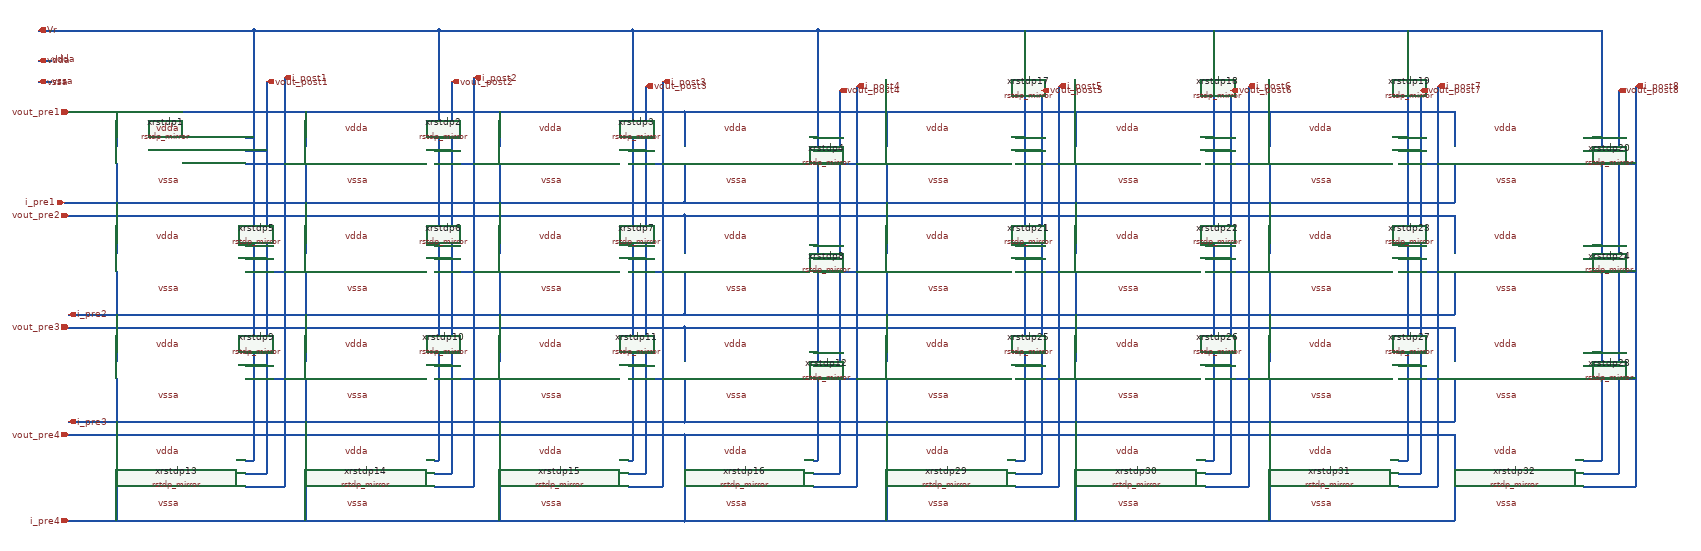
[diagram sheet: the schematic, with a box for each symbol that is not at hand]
v {xschem version=3.4.6RC file_version=1.2
}
G {}
K {}
V {}
S {}
E {}
N 1130 -130 1130 -50 {
lab=vout_pre1}
N -310 -130 1130 -130 {
lab=vout_pre1}
N 1130 110 1130 200 {
lab=vout_pre2}
N -300 110 1130 110 {
lab=vout_pre2}
N 1130 620 1130 700 {
lab=vout_pre4}
N -300 620 1130 620 {
lab=vout_pre4}
N -300 370 1130 370 {
lab=vout_pre3}
N 1130 370 1130 450 {
lab=vout_pre3}
N -190 -130 -190 -50 {
lab=vout_pre1}
N 250 -130 250 -50 {
lab=vout_pre1}
N 700 -130 700 -50 {
lab=vout_pre1}
N 700 110 700 200 {
lab=vout_pre2}
N 250 110 250 200 {
lab=vout_pre2}
N -190 110 -190 200 {
lab=vout_pre2}
N -190 370 -190 450 {
lab=vout_pre3}
N 250 370 250 450 {
lab=vout_pre3}
N 700 370 700 450 {
lab=vout_pre3}
N -190 620 -190 700 {
lab=vout_pre4}
N 250 620 250 700 {
lab=vout_pre4}
N 700 620 700 700 {
lab=vout_pre4}
N 160 -200 160 710 {
lab=vout_post1}
N 110 710 160 710 {
lab=vout_post1}
N 110 460 160 460 {
lab=vout_post1}
N 110 210 160 210 {
lab=vout_post1}
N 110 -40 160 -40 {
lab=vout_post1}
N 590 -200 590 710 {
lab=vout_post2}
N 550 710 590 710 {
lab=vout_post2}
N 550 460 590 460 {
lab=vout_post2}
N 550 210 590 210 {
lab=vout_post2}
N 550 -40 590 -40 {
lab=vout_post2}
N 1040 -190 1040 710 {
lab=vout_post3}
N 1000 710 1040 710 {
lab=vout_post3}
N 1000 460 1040 460 {
lab=vout_post3}
N 1000 210 1040 210 {
lab=vout_post3}
N 1000 -40 1040 -40 {
lab=vout_post3}
N 1490 -180 1490 710 {
lab=vout_post4}
N 1430 710 1490 710 {
lab=vout_post4}
N 1430 460 1490 460 {
lab=vout_post4}
N 1430 210 1490 210 {
lab=vout_post4}
N 1430 -40 1490 -40 {
lab=vout_post4}
N -310 80 1130 80 {
lab=i_pre1}
N 1130 -10 1130 80 {
lab=i_pre1}
N 700 -10 700 80 {
lab=i_pre1}
N 250 -10 250 80 {
lab=i_pre1}
N -190 -10 -190 80 {
lab=i_pre1}
N -300 340 1130 340 {
lab=i_pre2}
N 1130 240 1130 340 {
lab=i_pre2}
N 700 240 700 340 {
lab=i_pre2}
N 250 240 250 340 {
lab=i_pre2}
N -190 240 -190 340 {
lab=i_pre2}
N -300 820 1130 820 {
lab=i_pre4}
N 1130 740 1130 820 {
lab=i_pre4}
N 700 740 700 820 {
lab=i_pre4}
N 250 740 250 820 {
lab=i_pre4}
N -190 740 -190 820 {
lab=i_pre4}
N -300 590 1130 590 {
lab=i_pre3}
N 1130 490 1130 590 {
lab=i_pre3}
N 700 490 700 590 {
lab=i_pre3}
N 250 490 250 590 {
lab=i_pre3}
N -190 490 -190 590 {
lab=i_pre3}
N 200 -210 200 740 {
lab=i_post1}
N 110 740 200 740 {
lab=i_post1}
N 110 -10 200 -10 {
lab=i_post1}
N 110 240 200 240 {
lab=i_post1}
N 110 490 200 490 {
lab=i_post1}
N 640 -210 640 740 {
lab=i_post2}
N 550 740 640 740 {
lab=i_post2}
N 550 490 640 490 {
lab=i_post2}
N 550 240 640 240 {
lab=i_post2}
N 550 -10 640 -10 {
lab=i_post2}
N 1080 -200 1080 740 {
lab=i_post3}
N 1000 740 1080 740 {
lab=i_post3}
N 1000 490 1080 490 {
lab=i_post3}
N 1000 240 1080 240 {
lab=i_post3}
N 1000 -10 1080 -10 {
lab=i_post3}
N 1530 -190 1530 740 {
lab=i_post4}
N 1430 740 1530 740 {
lab=i_post4}
N 1430 490 1530 490 {
lab=i_post4}
N 1430 240 1530 240 {
lab=i_post4}
N 1430 -10 1530 -10 {
lab=i_post4}
N -370 -250 -340 -250 {
lab=vdda}
N -370 -200 -340 -200 {
lab=vssa}
N -370 -320 -350 -320 {
lab=Vr}
N 110 -70 120 -70 {
lab=Vr}
N 550 -70 560 -70 {
lab=Vr}
N 1000 -70 1010 -70 {
lab=Vr}
N 1430 -70 1440 -70 {
lab=Vr}
N 1430 180 1440 180 {
lab=Vr}
N 1000 180 1010 180 {
lab=Vr}
N 550 180 560 180 {
lab=Vr}
N 110 180 120 180 {
lab=Vr}
N 110 430 120 430 {
lab=Vr}
N 550 430 560 430 {
lab=Vr}
N 1000 430 1010 430 {
lab=Vr}
N 1430 430 1440 430 {
lab=Vr}
N 1430 680 1440 680 {
lab=Vr}
N 1000 680 1010 680 {
lab=Vr}
N 550 680 560 680 {
lab=Vr}
N 110 680 120 680 {
lab=Vr}
N -350 -320 130 -320 {
lab=Vr}
N 130 -320 130 680 {
lab=Vr}
N 120 680 130 680 {
lab=Vr}
N 120 430 130 430 {
lab=Vr}
N 120 180 130 180 {
lab=Vr}
N 120 -70 130 -70 {
lab=Vr}
N 560 -320 560 680 {
lab=Vr}
N 130 -320 560 -320 {
lab=Vr}
N 1010 -320 1010 680 {
lab=Vr}
N 560 -320 1010 -320 {
lab=Vr}
N 1440 -320 1440 680 {
lab=Vr}
N 1010 -320 1440 -320 {
lab=Vr}
N 1130 80 2920 80 {
lab=i_pre1}
N 2920 -10 2920 80 {
lab=i_pre1}
N 2490 -10 2490 80 {
lab=i_pre1}
N 2040 -10 2040 80 {
lab=i_pre1}
N 1600 -10 1600 80 {
lab=i_pre1}
N 1130 340 2920 340 {
lab=i_pre2}
N 2920 240 2920 340 {
lab=i_pre2}
N 2490 240 2490 340 {
lab=i_pre2}
N 2040 240 2040 340 {
lab=i_pre2}
N 1600 240 1600 340 {
lab=i_pre2}
N 1130 590 2920 590 {
lab=i_pre3}
N 2920 490 2920 590 {
lab=i_pre3}
N 2490 490 2490 590 {
lab=i_pre3}
N 2040 490 2040 590 {
lab=i_pre3}
N 1600 490 1600 590 {
lab=i_pre3}
N 1130 820 2920 820 {
lab=i_pre4}
N 2920 740 2920 820 {
lab=i_pre4}
N 2490 740 2490 820 {
lab=i_pre4}
N 2040 740 2040 820 {
lab=i_pre4}
N 1600 740 1600 820 {
lab=i_pre4}
N 1440 -320 3260 -320 {
lab=Vr}
N 3260 -320 3260 680 {
lab=Vr}
N 3220 680 3260 680 {
lab=Vr}
N 3220 430 3260 430 {
lab=Vr}
N 3220 180 3260 180 {
lab=Vr}
N 3220 -70 3260 -70 {
lab=Vr}
N 2810 -320 2810 680 {
lab=Vr}
N 2790 -70 2810 -70 {
lab=Vr}
N 2790 180 2810 180 {
lab=Vr}
N 2790 430 2810 430 {
lab=Vr}
N 2790 680 2810 680 {
lab=Vr}
N 2360 -320 2360 680 {
lab=Vr}
N 2340 680 2360 680 {
lab=Vr}
N 2340 430 2360 430 {
lab=Vr}
N 2340 180 2360 180 {
lab=Vr}
N 2340 -70 2360 -70 {
lab=Vr}
N 1920 -320 1920 680 {
lab=Vr}
N 1900 680 1920 680 {
lab=Vr}
N 1900 430 1920 430 {
lab=Vr}
N 1900 180 1920 180 {
lab=Vr}
N 1900 -70 1920 -70 {
lab=Vr}
N 1960 -180 1960 710 {
lab=vout_post5}
N 2000 -190 2000 740 {
lab=i_post5}
N 1900 -40 1960 -40 {
lab=vout_post5}
N 1900 -10 2000 -10 {
lab=i_post5}
N 1900 210 1960 210 {
lab=vout_post5}
N 1900 240 2000 240 {
lab=i_post5}
N 1900 460 1960 460 {
lab=vout_post5}
N 1900 490 2000 490 {
lab=i_post5}
N 1900 710 1960 710 {
lab=vout_post5}
N 1900 740 2000 740 {
lab=i_post5}
N 2400 -180 2400 710 {
lab=vout_post6}
N 2440 -190 2440 740 {
lab=i_post6}
N 2340 -40 2400 -40 {
lab=vout_post6}
N 2340 -10 2440 -10 {
lab=i_post6}
N 2340 210 2400 210 {
lab=vout_post6}
N 2340 240 2440 240 {
lab=i_post6}
N 2340 460 2400 460 {
lab=vout_post6}
N 2340 490 2440 490 {
lab=i_post6}
N 2340 710 2400 710 {
lab=vout_post6}
N 2340 740 2440 740 {
lab=i_post6}
N 2840 -180 2840 710 {
lab=vout_post7}
N 2880 -190 2880 740 {
lab=i_post7}
N 2790 -40 2840 -40 {
lab=vout_post7}
N 2790 -10 2880 -10 {
lab=i_post7}
N 2790 210 2840 210 {
lab=vout_post7}
N 2790 240 2880 240 {
lab=i_post7}
N 2790 460 2840 460 {
lab=vout_post7}
N 2790 490 2880 490 {
lab=i_post7}
N 2790 710 2840 710 {
lab=vout_post7}
N 2790 740 2880 740 {
lab=i_post7}
N 3300 -180 3300 710 {
lab=vout_post8}
N 3340 -190 3340 740 {
lab=i_post8}
N 3220 -40 3300 -40 {
lab=vout_post8}
N 3220 -10 3340 -10 {
lab=i_post8}
N 3220 210 3300 210 {
lab=vout_post8}
N 3220 240 3340 240 {
lab=i_post8}
N 3220 460 3300 460 {
lab=vout_post8}
N 3220 490 3340 490 {
lab=i_post8}
N 3220 710 3300 710 {
lab=vout_post8}
N 3220 740 3340 740 {
lab=i_post8}
N 1130 -130 2920 -130 {
lab=vout_pre1}
N 2920 -130 2920 -50 {
lab=vout_pre1}
N 1600 -130 1600 -50 {
lab=vout_pre1}
N 2040 -130 2040 -50 {
lab=vout_pre1}
N 2490 -130 2490 -50 {
lab=vout_pre1}
N 1130 110 2920 110 {
lab=vout_pre2}
N 1600 110 1600 200 {
lab=vout_pre2}
N 2040 110 2040 200 {
lab=vout_pre2}
N 2490 110 2490 200 {
lab=vout_pre2}
N 2920 110 2920 200 {
lab=vout_pre2}
N 1130 370 2920 370 {
lab=vout_pre3}
N 1600 370 1600 450 {
lab=vout_pre3}
N 2040 370 2040 450 {
lab=vout_pre3}
N 2490 370 2490 450 {
lab=vout_pre3}
N 2920 370 2920 450 {
lab=vout_pre3}
N 1130 620 2920 620 {
lab=vout_pre4}
N 1600 620 1600 700 {
lab=vout_pre4}
N 2040 620 2040 700 {
lab=vout_pre4}
N 2490 620 2490 700 {
lab=vout_pre4}
N 2920 620 2920 700 {
lab=vout_pre4}
C {Synapse/rstdp_mirror.sym} -40 -50 0 0 {name=xrstdp1}
C {devices/ipin.sym} -300 -130 0 0 {name=p1 lab=vout_pre1}
C {devices/opin.sym} 160 -200 3 0 {name=p5 lab=vout_post1}
C {devices/ipin.sym} -310 80 0 0 {name=p6 lab=i_pre1}
C {devices/iopin.sym} -370 -250 0 1 {name=p7 lab=vdda}
C {devices/iopin.sym} -370 -200 0 1 {name=p8 lab=vssa}
C {Synapse/rstdp_mirror.sym} 400 -50 0 0 {name=xrstdp2}
C {Synapse/rstdp_mirror.sym} 850 -50 0 0 {name=xrstdp3}
C {Synapse/rstdp_mirror.sym} 1280 -50 0 0 {name=xrstdp4}
C {devices/opin.sym} 200 -210 3 0 {name=p9 lab=i_post1}
C {Synapse/rstdp_mirror.sym} -40 200 0 0 {name=xrstdp5}
C {Synapse/rstdp_mirror.sym} 400 200 0 0 {name=xrstdp6}
C {Synapse/rstdp_mirror.sym} 850 200 0 0 {name=xrstdp7}
C {Synapse/rstdp_mirror.sym} 1280 200 0 0 {name=xrstdp8}
C {Synapse/rstdp_mirror.sym} -40 450 0 0 {name=xrstdp9}
C {Synapse/rstdp_mirror.sym} 400 450 0 0 {name=xrstdp10}
C {Synapse/rstdp_mirror.sym} 850 450 0 0 {name=xrstdp11}
C {Synapse/rstdp_mirror.sym} 1280 450 0 0 {name=xrstdp12}
C {Synapse/rstdp_mirror.sym} -40 700 0 0 {name=xrstdp13}
C {Synapse/rstdp_mirror.sym} 400 700 0 0 {name=xrstdp14}
C {Synapse/rstdp_mirror.sym} 850 700 0 0 {name=xrstdp15}
C {Synapse/rstdp_mirror.sym} 1280 700 0 0 {name=xrstdp16}
C {devices/opin.sym} 1080 -200 3 0 {name=p11 lab=i_post3}
C {devices/opin.sym} 1530 -190 3 0 {name=p12 lab=i_post4}
C {devices/ipin.sym} -300 340 2 1 {name=p13 lab=i_pre2}
C {devices/ipin.sym} -300 590 2 1 {name=p14 lab=i_pre3}
C {devices/ipin.sym} -300 820 0 0 {name=p15 lab=i_pre4}
C {devices/ipin.sym} -300 110 0 0 {name=p2 lab=vout_pre2}
C {devices/ipin.sym} -300 370 0 0 {name=p3 lab=vout_pre3}
C {devices/ipin.sym} -300 620 0 0 {name=p4 lab=vout_pre4}
C {devices/opin.sym} 590 -200 3 0 {name=p16 lab=vout_post2}
C {devices/opin.sym} 1040 -190 3 0 {name=p17 lab=vout_post3}
C {devices/opin.sym} 1490 -180 3 0 {name=p18 lab=vout_post4}
C {devices/opin.sym} 640 -210 3 0 {name=p19 lab=i_post2}
C {devices/iopin.sym} -370 -320 0 1 {name=p10 lab=Vr}
C {devices/lab_pin.sym} -40 -90 1 0 {name=p20 sig_type=std_logic lab=vdda}
C {devices/lab_pin.sym} -40 160 1 0 {name=p21 sig_type=std_logic lab=vdda}
C {devices/lab_pin.sym} -40 410 1 0 {name=p22 sig_type=std_logic lab=vdda}
C {devices/lab_pin.sym} -40 660 1 0 {name=p23 sig_type=std_logic lab=vdda}
C {devices/lab_pin.sym} 400 -90 1 0 {name=p24 sig_type=std_logic lab=vdda}
C {devices/lab_pin.sym} 400 160 1 0 {name=p25 sig_type=std_logic lab=vdda}
C {devices/lab_pin.sym} 400 410 1 0 {name=p26 sig_type=std_logic lab=vdda}
C {devices/lab_pin.sym} 400 660 1 0 {name=p27 sig_type=std_logic lab=vdda}
C {devices/lab_pin.sym} 850 -90 1 0 {name=p28 sig_type=std_logic lab=vdda}
C {devices/lab_pin.sym} 850 160 1 0 {name=p29 sig_type=std_logic lab=vdda}
C {devices/lab_pin.sym} 850 410 1 0 {name=p30 sig_type=std_logic lab=vdda}
C {devices/lab_pin.sym} 850 660 1 0 {name=p31 sig_type=std_logic lab=vdda}
C {devices/lab_pin.sym} 1280 -90 1 0 {name=p32 sig_type=std_logic lab=vdda}
C {devices/lab_pin.sym} 1280 160 1 0 {name=p33 sig_type=std_logic lab=vdda}
C {devices/lab_pin.sym} 1280 410 1 0 {name=p34 sig_type=std_logic lab=vdda}
C {devices/lab_pin.sym} 1280 660 1 0 {name=p35 sig_type=std_logic lab=vdda}
C {devices/lab_pin.sym} -40 30 3 0 {name=p36 sig_type=std_logic lab=vssa}
C {devices/lab_pin.sym} -40 280 3 0 {name=p37 sig_type=std_logic lab=vssa}
C {devices/lab_pin.sym} -40 530 3 0 {name=p38 sig_type=std_logic lab=vssa}
C {devices/lab_pin.sym} -40 780 3 0 {name=p39 sig_type=std_logic lab=vssa}
C {devices/lab_pin.sym} 400 30 3 0 {name=p40 sig_type=std_logic lab=vssa}
C {devices/lab_pin.sym} 400 280 3 0 {name=p41 sig_type=std_logic lab=vssa}
C {devices/lab_pin.sym} 400 530 3 0 {name=p42 sig_type=std_logic lab=vssa}
C {devices/lab_pin.sym} 400 780 3 0 {name=p43 sig_type=std_logic lab=vssa}
C {devices/lab_pin.sym} 850 30 3 0 {name=p44 sig_type=std_logic lab=vssa}
C {devices/lab_pin.sym} 850 280 3 0 {name=p45 sig_type=std_logic lab=vssa}
C {devices/lab_pin.sym} 850 530 3 0 {name=p46 sig_type=std_logic lab=vssa}
C {devices/lab_pin.sym} 850 780 3 0 {name=p47 sig_type=std_logic lab=vssa}
C {devices/lab_pin.sym} 1280 30 3 0 {name=p48 sig_type=std_logic lab=vssa}
C {devices/lab_pin.sym} 1280 280 3 0 {name=p49 sig_type=std_logic lab=vssa}
C {devices/lab_pin.sym} 1280 530 3 0 {name=p50 sig_type=std_logic lab=vssa}
C {devices/lab_pin.sym} 1280 780 3 0 {name=p51 sig_type=std_logic lab=vssa}
C {devices/lab_pin.sym} -340 -250 2 0 {name=p52 sig_type=std_logic lab=vdda}
C {devices/lab_pin.sym} -340 -200 2 0 {name=p54 sig_type=std_logic lab=vssa}
C {Synapse/rstdp_mirror.sym} 1750 -50 0 0 {name=xrstdp17}
C {Synapse/rstdp_mirror.sym} 2190 -50 0 0 {name=xrstdp18}
C {Synapse/rstdp_mirror.sym} 2640 -50 0 0 {name=xrstdp19}
C {Synapse/rstdp_mirror.sym} 3070 -50 0 0 {name=xrstdp20}
C {Synapse/rstdp_mirror.sym} 1750 200 0 0 {name=xrstdp21}
C {Synapse/rstdp_mirror.sym} 2190 200 0 0 {name=xrstdp22}
C {Synapse/rstdp_mirror.sym} 2640 200 0 0 {name=xrstdp23}
C {Synapse/rstdp_mirror.sym} 3070 200 0 0 {name=xrstdp24}
C {Synapse/rstdp_mirror.sym} 1750 450 0 0 {name=xrstdp25}
C {Synapse/rstdp_mirror.sym} 2190 450 0 0 {name=xrstdp26}
C {Synapse/rstdp_mirror.sym} 2640 450 0 0 {name=xrstdp27}
C {Synapse/rstdp_mirror.sym} 3070 450 0 0 {name=xrstdp28}
C {Synapse/rstdp_mirror.sym} 1750 700 0 0 {name=xrstdp29}
C {Synapse/rstdp_mirror.sym} 2190 700 0 0 {name=xrstdp30}
C {Synapse/rstdp_mirror.sym} 2640 700 0 0 {name=xrstdp31}
C {Synapse/rstdp_mirror.sym} 3070 700 0 0 {name=xrstdp32}
C {devices/lab_pin.sym} 1750 -90 1 0 {name=p53 sig_type=std_logic lab=vdda}
C {devices/lab_pin.sym} 2190 -90 1 0 {name=p55 sig_type=std_logic lab=vdda}
C {devices/lab_pin.sym} 1750 160 1 0 {name=p56 sig_type=std_logic lab=vdda}
C {devices/lab_pin.sym} 2190 160 1 0 {name=p57 sig_type=std_logic lab=vdda}
C {devices/lab_pin.sym} 2640 -90 1 0 {name=p58 sig_type=std_logic lab=vdda}
C {devices/lab_pin.sym} 2640 160 1 0 {name=p59 sig_type=std_logic lab=vdda}
C {devices/lab_pin.sym} 3070 -90 1 0 {name=p60 sig_type=std_logic lab=vdda}
C {devices/lab_pin.sym} 3070 160 1 0 {name=p61 sig_type=std_logic lab=vdda}
C {devices/lab_pin.sym} 3070 410 1 0 {name=p62 sig_type=std_logic lab=vdda}
C {devices/lab_pin.sym} 2640 410 1 0 {name=p63 sig_type=std_logic lab=vdda}
C {devices/lab_pin.sym} 2190 410 1 0 {name=p64 sig_type=std_logic lab=vdda}
C {devices/lab_pin.sym} 1750 410 1 0 {name=p65 sig_type=std_logic lab=vdda}
C {devices/lab_pin.sym} 1750 660 1 0 {name=p66 sig_type=std_logic lab=vdda}
C {devices/lab_pin.sym} 2190 660 1 0 {name=p67 sig_type=std_logic lab=vdda}
C {devices/lab_pin.sym} 2640 660 1 0 {name=p68 sig_type=std_logic lab=vdda}
C {devices/lab_pin.sym} 3070 660 1 0 {name=p69 sig_type=std_logic lab=vdda}
C {devices/lab_pin.sym} 1750 30 3 0 {name=p70 sig_type=std_logic lab=vssa}
C {devices/lab_pin.sym} 2190 30 3 0 {name=p71 sig_type=std_logic lab=vssa}
C {devices/lab_pin.sym} 1750 280 3 0 {name=p72 sig_type=std_logic lab=vssa}
C {devices/lab_pin.sym} 2190 280 3 0 {name=p73 sig_type=std_logic lab=vssa}
C {devices/lab_pin.sym} 2640 30 3 0 {name=p74 sig_type=std_logic lab=vssa}
C {devices/lab_pin.sym} 2640 280 3 0 {name=p75 sig_type=std_logic lab=vssa}
C {devices/lab_pin.sym} 3070 30 3 0 {name=p76 sig_type=std_logic lab=vssa}
C {devices/lab_pin.sym} 3070 280 3 0 {name=p77 sig_type=std_logic lab=vssa}
C {devices/lab_pin.sym} 3070 530 3 0 {name=p78 sig_type=std_logic lab=vssa}
C {devices/lab_pin.sym} 3070 780 3 0 {name=p79 sig_type=std_logic lab=vssa}
C {devices/lab_pin.sym} 2640 780 3 0 {name=p80 sig_type=std_logic lab=vssa}
C {devices/lab_pin.sym} 2640 530 3 0 {name=p81 sig_type=std_logic lab=vssa}
C {devices/lab_pin.sym} 2190 530 3 0 {name=p82 sig_type=std_logic lab=vssa}
C {devices/lab_pin.sym} 1750 530 3 0 {name=p83 sig_type=std_logic lab=vssa}
C {devices/lab_pin.sym} 1750 780 3 0 {name=p84 sig_type=std_logic lab=vssa}
C {devices/lab_pin.sym} 2190 780 3 0 {name=p85 sig_type=std_logic lab=vssa}
C {devices/opin.sym} 2000 -190 3 0 {name=p86 lab=i_post5}
C {devices/opin.sym} 1960 -180 3 0 {name=p87 lab=vout_post5}
C {devices/opin.sym} 2440 -190 3 0 {name=p88 lab=i_post6}
C {devices/opin.sym} 2400 -180 3 0 {name=p89 lab=vout_post6}
C {devices/opin.sym} 2880 -190 3 0 {name=p90 lab=i_post7}
C {devices/opin.sym} 2840 -180 3 0 {name=p91 lab=vout_post7}
C {devices/opin.sym} 3340 -190 3 0 {name=p92 lab=i_post8}
C {devices/opin.sym} 3300 -180 3 0 {name=p93 lab=vout_post8}
